VERSION 5.8 ;
BUSBITCHARS "[]" ;
DIVIDERCHAR "/" ;
UNITS
    DATABASE MICRONS 1000 ;
END UNITS

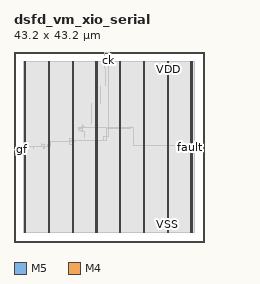
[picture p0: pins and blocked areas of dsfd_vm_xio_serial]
MACRO dsfd_vm_xio_serial
  FOREIGN dsfd_vm_xio_serial 0 0 ;
  CLASS BLOCK ;
  SIZE 43.2 BY 43.2 ;
  PIN ck
    DIRECTION INPUT ;
    USE SIGNAL ;
    PORT
      LAYER M5 ;
        RECT  21.552 43.116 21.576 43.2 ;
    END
  END ck
  PIN fault
    DIRECTION OUTPUT ;
    USE SIGNAL ;
    PORT
      LAYER M4 ;
        RECT  43.116 21.552 43.2 21.576 ;
    END
  END fault
  PIN gf
    DIRECTION INPUT ;
    USE SIGNAL ;
    PORT
      LAYER M4 ;
        RECT  0 20.976 0.084 21 ;
    END
  END gf
  PIN qSWs[0]
    DIRECTION INPUT ;
    USE SIGNAL ;
    PORT
      LAYER M4 ;
        RECT  0 21.264 0.084 21.288 ;
    END
  END qSWs[0]
  PIN qSWs[1]
    DIRECTION INPUT ;
    USE SIGNAL ;
    PORT
      LAYER M4 ;
        RECT  0 21.36 0.084 21.384 ;
    END
  END qSWs[1]
  PIN qSWs[2]
    DIRECTION INPUT ;
    USE SIGNAL ;
    PORT
      LAYER M4 ;
        RECT  0 21.456 0.084 21.48 ;
    END
  END qSWs[2]
  PIN qf
    DIRECTION INPUT ;
    USE SIGNAL ;
    PORT
      LAYER M4 ;
        RECT  0 21.072 0.084 21.096 ;
    END
  END qf
  PIN qo_v
    DIRECTION INPUT ;
    USE SIGNAL ;
    PORT
      LAYER M4 ;
        RECT  0 21.168 0.084 21.192 ;
    END
  END qo_v
  PIN rst_n
    DIRECTION INPUT ;
    USE SIGNAL ;
    PORT
      LAYER M5 ;
        RECT  21.648 43.116 21.672 43.2 ;
    END
  END rst_n
  PIN VDD
    DIRECTION INOUT ;
    USE POWER ;
    PORT
      LAYER M5 ;
        RECT  40.392 2.151 40.512 41.049 ;
        RECT  34.992 2.151 35.112 41.049 ;
        RECT  29.592 2.151 29.712 41.049 ;
        RECT  24.192 2.151 24.312 41.049 ;
        RECT  18.792 2.151 18.912 41.049 ;
        RECT  13.392 2.151 13.512 41.049 ;
        RECT  7.992 2.151 8.112 41.049 ;
        RECT  2.592 2.151 2.712 41.049 ;
    END
  END VDD
  PIN VSS
    DIRECTION INOUT ;
    USE GROUND ;
    PORT
      LAYER M5 ;
        RECT  40.2 2.137 40.32 41.063 ;
        RECT  34.8 2.137 34.92 41.063 ;
        RECT  29.4 2.137 29.52 41.063 ;
        RECT  24 2.137 24.12 41.063 ;
        RECT  18.6 2.137 18.72 41.063 ;
        RECT  13.2 2.137 13.32 41.063 ;
        RECT  7.8 2.137 7.92 41.063 ;
        RECT  2.4 2.137 2.52 41.063 ;
    END
  END VSS
  OBS
    LAYER RVTN ;
     RECT  2.16 2.16 41.04 2.295 ;
     RECT  2.16 2.565 41.04 2.835 ;
     RECT  2.16 3.105 41.04 3.375 ;
     RECT  2.16 3.645 41.04 3.915 ;
     RECT  2.16 4.185 41.04 4.455 ;
     RECT  2.16 4.725 41.04 4.995 ;
     RECT  2.16 5.265 41.04 5.535 ;
     RECT  2.16 5.805 41.04 6.075 ;
     RECT  2.16 6.345 41.04 6.615 ;
     RECT  2.16 6.885 41.04 7.155 ;
     RECT  2.16 7.425 41.04 7.695 ;
     RECT  2.16 7.965 41.04 8.235 ;
     RECT  2.16 8.505 41.04 8.775 ;
     RECT  2.16 9.045 41.04 9.315 ;
     RECT  2.16 9.585 41.04 9.855 ;
     RECT  2.16 10.125 41.04 10.395 ;
     RECT  2.16 10.665 41.04 10.935 ;
     RECT  2.16 11.205 41.04 11.475 ;
     RECT  2.16 11.745 41.04 12.015 ;
     RECT  2.16 12.285 41.04 12.555 ;
     RECT  2.16 12.825 41.04 13.095 ;
     RECT  2.16 13.365 41.04 13.635 ;
     RECT  2.16 13.905 41.04 14.175 ;
     RECT  2.16 14.445 41.04 14.715 ;
     RECT  2.16 14.985 41.04 15.255 ;
     RECT  2.16 15.525 41.04 15.795 ;
     RECT  2.16 16.065 41.04 16.335 ;
     RECT  2.16 16.605 41.04 16.875 ;
     RECT  2.16 17.145 41.04 17.415 ;
     RECT  2.16 17.685 41.04 17.955 ;
     RECT  2.16 18.225 41.04 18.495 ;
     RECT  2.16 18.765 41.04 19.035 ;
     RECT  2.16 19.305 41.04 19.575 ;
     RECT  2.16 19.845 41.04 20.115 ;
     RECT  2.16 20.385 41.04 20.655 ;
     RECT  2.16 20.925 41.04 21.195 ;
     RECT  2.16 21.465 41.04 21.735 ;
     RECT  2.16 22.005 41.04 22.275 ;
     RECT  2.16 22.545 41.04 22.815 ;
     RECT  2.16 23.085 41.04 23.355 ;
     RECT  2.16 23.625 41.04 23.895 ;
     RECT  2.16 24.165 41.04 24.435 ;
     RECT  2.16 24.705 41.04 24.975 ;
     RECT  2.16 25.245 41.04 25.515 ;
     RECT  2.16 25.785 41.04 26.055 ;
     RECT  2.16 26.325 41.04 26.595 ;
     RECT  2.16 26.865 41.04 27.135 ;
     RECT  2.16 27.405 41.04 27.675 ;
     RECT  2.16 27.945 41.04 28.215 ;
     RECT  2.16 28.485 41.04 28.755 ;
     RECT  2.16 29.025 41.04 29.295 ;
     RECT  2.16 29.565 41.04 29.835 ;
     RECT  2.16 30.105 41.04 30.375 ;
     RECT  2.16 30.645 41.04 30.915 ;
     RECT  2.16 31.185 41.04 31.455 ;
     RECT  2.16 31.725 41.04 31.995 ;
     RECT  2.16 32.265 41.04 32.535 ;
     RECT  2.16 32.805 41.04 33.075 ;
     RECT  2.16 33.345 41.04 33.615 ;
     RECT  2.16 33.885 41.04 34.155 ;
     RECT  2.16 34.425 41.04 34.695 ;
     RECT  2.16 34.965 41.04 35.235 ;
     RECT  2.16 35.505 41.04 35.775 ;
     RECT  2.16 36.045 41.04 36.315 ;
     RECT  2.16 36.585 41.04 36.855 ;
     RECT  2.16 37.125 41.04 37.395 ;
     RECT  2.16 37.665 41.04 37.935 ;
     RECT  2.16 38.205 41.04 38.475 ;
     RECT  2.16 38.745 41.04 39.015 ;
     RECT  2.16 39.285 41.04 39.555 ;
     RECT  2.16 39.825 41.04 40.095 ;
     RECT  2.16 40.365 41.04 40.635 ;
     RECT  2.16 40.905 41.04 41.04 ;
    LAYER RVTP ;
     RECT  2.16 2.295 41.04 2.565 ;
     RECT  2.16 2.835 41.04 3.105 ;
     RECT  2.16 3.375 41.04 3.645 ;
     RECT  2.16 3.915 41.04 4.185 ;
     RECT  2.16 4.455 41.04 4.725 ;
     RECT  2.16 4.995 41.04 5.265 ;
     RECT  2.16 5.535 41.04 5.805 ;
     RECT  2.16 6.075 41.04 6.345 ;
     RECT  2.16 6.615 41.04 6.885 ;
     RECT  2.16 7.155 41.04 7.425 ;
     RECT  2.16 7.695 41.04 7.965 ;
     RECT  2.16 8.235 41.04 8.505 ;
     RECT  2.16 8.775 41.04 9.045 ;
     RECT  2.16 9.315 41.04 9.585 ;
     RECT  2.16 9.855 41.04 10.125 ;
     RECT  2.16 10.395 41.04 10.665 ;
     RECT  2.16 10.935 41.04 11.205 ;
     RECT  2.16 11.475 41.04 11.745 ;
     RECT  2.16 12.015 41.04 12.285 ;
     RECT  2.16 12.555 41.04 12.825 ;
     RECT  2.16 13.095 41.04 13.365 ;
     RECT  2.16 13.635 41.04 13.905 ;
     RECT  2.16 14.175 41.04 14.445 ;
     RECT  2.16 14.715 41.04 14.985 ;
     RECT  2.16 15.255 41.04 15.525 ;
     RECT  2.16 15.795 41.04 16.065 ;
     RECT  2.16 16.335 41.04 16.605 ;
     RECT  2.16 16.875 41.04 17.145 ;
     RECT  2.16 17.415 41.04 17.685 ;
     RECT  2.16 17.955 41.04 18.225 ;
     RECT  2.16 18.495 41.04 18.765 ;
     RECT  2.16 19.035 41.04 19.305 ;
     RECT  2.16 19.575 41.04 19.845 ;
     RECT  2.16 20.115 41.04 20.385 ;
     RECT  2.16 20.655 41.04 20.925 ;
     RECT  2.16 21.195 41.04 21.465 ;
     RECT  2.16 21.735 41.04 22.005 ;
     RECT  2.16 22.275 41.04 22.545 ;
     RECT  2.16 22.815 41.04 23.085 ;
     RECT  2.16 23.355 41.04 23.625 ;
     RECT  2.16 23.895 41.04 24.165 ;
     RECT  2.16 24.435 41.04 24.705 ;
     RECT  2.16 24.975 41.04 25.245 ;
     RECT  2.16 25.515 41.04 25.785 ;
     RECT  2.16 26.055 41.04 26.325 ;
     RECT  2.16 26.595 41.04 26.865 ;
     RECT  2.16 27.135 41.04 27.405 ;
     RECT  2.16 27.675 41.04 27.945 ;
     RECT  2.16 28.215 41.04 28.485 ;
     RECT  2.16 28.755 41.04 29.025 ;
     RECT  2.16 29.295 41.04 29.565 ;
     RECT  2.16 29.835 41.04 30.105 ;
     RECT  2.16 30.375 41.04 30.645 ;
     RECT  2.16 30.915 41.04 31.185 ;
     RECT  2.16 31.455 41.04 31.725 ;
     RECT  2.16 31.995 41.04 32.265 ;
     RECT  2.16 32.535 41.04 32.805 ;
     RECT  2.16 33.075 41.04 33.345 ;
     RECT  2.16 33.615 41.04 33.885 ;
     RECT  2.16 34.155 41.04 34.425 ;
     RECT  2.16 34.695 41.04 34.965 ;
     RECT  2.16 35.235 41.04 35.505 ;
     RECT  2.16 35.775 41.04 36.045 ;
     RECT  2.16 36.315 41.04 36.585 ;
     RECT  2.16 36.855 41.04 37.125 ;
     RECT  2.16 37.395 41.04 37.665 ;
     RECT  2.16 37.935 41.04 38.205 ;
     RECT  2.16 38.475 41.04 38.745 ;
     RECT  2.16 39.015 41.04 39.285 ;
     RECT  2.16 39.555 41.04 39.825 ;
     RECT  2.16 40.095 41.04 40.365 ;
     RECT  2.16 40.635 41.04 40.905 ;
    LAYER M1 ;
     RECT  2.16 2.151 41.04 41.049 ;
    LAYER M2 ;
     RECT  0.535 20.862 2.16 20.88 ;
     RECT  2.16 2.151 41.04 41.049 ;
     RECT  41.04 21.546 42.179 21.564 ;
    LAYER M3 ;
     RECT  2.415 2.143 2.505 2.413 ;
     RECT  7.815 2.143 7.905 2.413 ;
     RECT  13.215 2.143 13.305 2.413 ;
     RECT  18.615 2.143 18.705 2.413 ;
     RECT  24.015 2.143 24.105 2.413 ;
     RECT  29.415 2.143 29.505 2.413 ;
     RECT  34.815 2.143 34.905 2.413 ;
     RECT  40.215 2.143 40.305 2.413 ;
     RECT  2.415 2.413 2.697 21.001 ;
     RECT  2.415 21.001 3.042 21.067 ;
     RECT  2.304 21.067 3.042 21.155 ;
     RECT  0.54 20.857 0.558 21.293 ;
     RECT  40.215 2.413 40.497 21.361 ;
     RECT  40.215 21.361 40.698 21.461 ;
     RECT  2.415 21.155 3.042 21.541 ;
     RECT  4.428 21.235 4.446 21.541 ;
     RECT  40.215 21.461 40.497 21.541 ;
     RECT  42.156 21.541 42.174 21.581 ;
     RECT  6.804 21.163 6.858 21.631 ;
     RECT  39.384 21.541 39.402 21.659 ;
     RECT  40.14 21.541 40.497 21.695 ;
     RECT  2.415 21.541 3.294 21.725 ;
     RECT  4.428 21.541 4.518 21.731 ;
     RECT  4.428 21.731 4.446 21.767 ;
     RECT  7.815 2.413 8.097 21.901 ;
     RECT  39.096 21.811 39.114 21.929 ;
     RECT  37.62 21.937 37.638 22.013 ;
     RECT  6.264 21.631 6.858 22.109 ;
     RECT  7.668 21.901 8.262 22.199 ;
     RECT  37.764 22.081 37.782 22.199 ;
     RECT  7.668 22.199 8.097 22.271 ;
     RECT  13.215 2.413 13.497 22.279 ;
     RECT  6.264 22.109 6.282 22.343 ;
     RECT  12.6 22.279 13.497 22.843 ;
     RECT  12.6 22.843 13.698 23.009 ;
     RECT  12.6 23.009 13.497 23.549 ;
     RECT  20.448 23.791 20.466 23.803 ;
     RECT  20.448 23.803 21.042 23.855 ;
     RECT  20.448 23.855 20.466 23.933 ;
     RECT  15.948 23.701 15.966 25.051 ;
     RECT  15.372 25.051 15.966 25.169 ;
     RECT  15.372 25.169 15.678 25.249 ;
     RECT  14.652 25.249 15.678 25.709 ;
     RECT  26.496 25.771 26.514 26.095 ;
     RECT  15.408 25.709 15.678 26.131 ;
     RECT  26.496 26.095 27.09 26.141 ;
     RECT  14.652 25.709 14.67 26.146 ;
     RECT  15.408 26.131 16.002 26.249 ;
     RECT  26.496 26.141 26.514 26.285 ;
     RECT  15.66 26.249 16.002 26.321 ;
     RECT  15.66 26.321 15.678 26.789 ;
     RECT  17.64 26.905 17.658 27.329 ;
     RECT  17.532 27.337 17.55 31.487 ;
     RECT  19.692 31.387 19.71 35.429 ;
     RECT  20.772 35.545 20.79 39.479 ;
     RECT  2.415 21.725 2.697 40.787 ;
     RECT  7.815 22.271 8.097 40.787 ;
     RECT  13.215 23.549 13.497 40.787 ;
     RECT  18.615 2.413 18.897 40.787 ;
     RECT  24.015 2.413 24.297 40.787 ;
     RECT  29.415 2.413 29.697 40.787 ;
     RECT  34.815 2.413 35.097 40.787 ;
     RECT  40.215 21.695 40.497 40.787 ;
     RECT  2.415 40.787 2.505 41.057 ;
     RECT  7.815 40.787 7.905 41.057 ;
     RECT  13.215 40.787 13.305 41.057 ;
     RECT  18.615 40.787 18.705 41.057 ;
     RECT  24.015 40.787 24.105 41.057 ;
     RECT  29.415 40.787 29.505 41.057 ;
     RECT  34.815 40.787 34.905 41.057 ;
     RECT  40.215 40.787 40.305 41.057 ;
     RECT  20.664 39.595 20.682 43.085 ;
    LAYER M4 ;
     RECT  0.06 20.976 2.408 21.384 ;
     RECT  2.408 2.148 2.512 41.052 ;
     RECT  2.512 2.418 2.704 40.782 ;
     RECT  2.704 21.168 2.765 21.72 ;
     RECT  2.765 21.696 7.808 21.72 ;
     RECT  7.808 2.148 7.912 41.052 ;
     RECT  7.912 2.418 8.104 40.782 ;
     RECT  8.104 21.696 8.243 22.872 ;
     RECT  8.243 22.848 13.208 22.872 ;
     RECT  13.208 2.148 13.312 41.052 ;
     RECT  13.312 2.418 13.504 40.782 ;
     RECT  13.504 22.848 13.709 23.064 ;
     RECT  13.709 23.04 18.608 23.064 ;
     RECT  14.641 26.112 18.608 26.136 ;
     RECT  18.608 2.148 18.712 41.052 ;
     RECT  18.712 2.418 18.904 40.782 ;
     RECT  18.904 23.04 20.437 23.064 ;
     RECT  18.904 26.112 21.013 26.136 ;
     RECT  20.437 23.04 21.059 23.928 ;
     RECT  21.059 23.904 21.587 23.928 ;
     RECT  20.653 43.056 21.683 43.08 ;
     RECT  21.013 25.776 24.008 26.136 ;
     RECT  24.008 2.148 24.112 41.052 ;
     RECT  24.112 2.418 24.304 40.782 ;
     RECT  24.304 25.776 26.525 26.136 ;
     RECT  26.525 26.112 27.107 26.136 ;
     RECT  27.061 21.984 29.408 22.008 ;
     RECT  29.408 2.148 29.512 41.052 ;
     RECT  29.512 2.418 29.704 40.782 ;
     RECT  29.704 21.984 34.808 22.008 ;
     RECT  34.808 2.148 34.912 41.052 ;
     RECT  34.912 2.418 35.104 40.782 ;
     RECT  35.104 21.984 37.649 22.008 ;
     RECT  40.208 2.148 40.312 41.052 ;
     RECT  40.312 2.418 40.504 40.782 ;
     RECT  42.145 21.552 43.164 21.576 ;
    LAYER M5 ;
     RECT  2.4 2.137 2.52 2.151 ;
     RECT  7.8 2.137 7.92 2.151 ;
     RECT  13.2 2.137 13.32 2.151 ;
     RECT  18.6 2.137 18.72 2.151 ;
     RECT  24 2.137 24.12 2.151 ;
     RECT  29.4 2.137 29.52 2.151 ;
     RECT  34.8 2.137 34.92 2.151 ;
     RECT  40.2 2.137 40.32 2.151 ;
     RECT  7.8 2.151 8.112 21.685 ;
     RECT  7.8 21.685 8.232 22.883 ;
     RECT  21.024 23.029 21.048 23.893 ;
     RECT  21.024 23.893 21.576 25.811 ;
     RECT  27.072 21.973 27.096 26.147 ;
     RECT  2.4 2.151 2.712 41.049 ;
     RECT  7.8 22.883 8.112 41.049 ;
     RECT  13.2 2.151 13.512 41.049 ;
     RECT  18.6 2.151 18.912 41.049 ;
     RECT  24 2.151 24.312 41.049 ;
     RECT  29.4 2.151 29.712 41.049 ;
     RECT  34.8 2.151 35.112 41.049 ;
     RECT  40.2 2.151 40.512 41.049 ;
     RECT  2.4 41.049 2.52 41.063 ;
     RECT  7.8 41.049 7.92 41.063 ;
     RECT  13.2 41.049 13.32 41.063 ;
     RECT  18.6 41.049 18.72 41.063 ;
     RECT  24 41.049 24.12 41.063 ;
     RECT  29.4 41.049 29.52 41.063 ;
     RECT  34.8 41.049 34.92 41.063 ;
     RECT  40.2 41.049 40.32 41.063 ;
     RECT  21.552 25.811 21.576 43.045 ;
     RECT  21.552 43.045 21.672 43.152 ;
  END
END dsfd_vm_xio_serial
END LIBRARY
